VERSION 5.7 ;
  NOWIREEXTENSIONATPIN ON ;
  DIVIDERCHAR "/" ;
  BUSBITCHARS "[]" ;
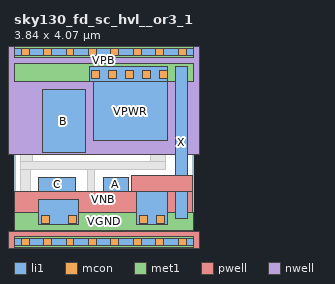
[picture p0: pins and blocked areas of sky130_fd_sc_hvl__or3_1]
MACRO sky130_fd_sc_hvl__or3_1
  CLASS BLOCK ;
  FOREIGN sky130_fd_sc_hvl__or3_1 ;
  ORIGIN 0.000 0.000 ;
  SIZE 3.840 BY 4.070 ;
  PIN A
    ANTENNAGATEAREA 0.420000 ;
    PORT
      LAYER li1 ;
        RECT 1.915 1.080 2.450 1.390 ;
    END
  END A
  PIN B
    ANTENNAGATEAREA 0.420000 ;
    PORT
      LAYER li1 ;
        RECT 0.605 1.910 1.535 3.260 ;
    END
  END B
  PIN C
    ANTENNAGATEAREA 0.420000 ;
    PORT
      LAYER li1 ;
        RECT 0.530 1.080 1.315 1.390 ;
    END
  END C
  PIN VGND
    USE GROUND ;
    PORT
      LAYER li1 ;
        RECT 0.530 0.365 1.385 0.910 ;
        RECT 2.620 0.365 3.290 1.325 ;
      LAYER mcon ;
        RECT 0.580 0.395 0.750 0.565 ;
        RECT 1.165 0.395 1.335 0.565 ;
        RECT 2.690 0.395 2.860 0.565 ;
        RECT 3.050 0.395 3.220 0.565 ;
      LAYER met1 ;
        RECT 0.000 0.255 3.840 0.625 ;
    END
  END VGND
  PIN VNB
    ANTENNADIFFAREA 0.652800 ;
    PORT
      LAYER pwell ;
        RECT 2.510 1.085 3.820 1.415 ;
        RECT 0.020 0.215 3.820 1.085 ;
        RECT -0.130 -0.215 3.970 0.215 ;
      LAYER li1 ;
        RECT 0.000 -0.085 3.840 0.085 ;
      LAYER mcon ;
        RECT 0.155 -0.085 0.325 0.085 ;
        RECT 0.635 -0.085 0.805 0.085 ;
        RECT 1.115 -0.085 1.285 0.085 ;
        RECT 1.595 -0.085 1.765 0.085 ;
        RECT 2.075 -0.085 2.245 0.085 ;
        RECT 2.555 -0.085 2.725 0.085 ;
        RECT 3.035 -0.085 3.205 0.085 ;
        RECT 3.515 -0.085 3.685 0.085 ;
      LAYER met1 ;
        RECT 0.000 -0.115 3.840 0.115 ;
    END
  END VNB
  PIN VPB
    ANTENNADIFFAREA 0.652800 ;
    PORT
      LAYER nwell ;
        RECT -0.330 1.885 4.170 4.485 ;
      LAYER li1 ;
        RECT 0.000 3.985 3.840 4.155 ;
      LAYER mcon ;
        RECT 0.155 3.985 0.325 4.155 ;
        RECT 0.635 3.985 0.805 4.155 ;
        RECT 1.115 3.985 1.285 4.155 ;
        RECT 1.595 3.985 1.765 4.155 ;
        RECT 2.075 3.985 2.245 4.155 ;
        RECT 2.555 3.985 2.725 4.155 ;
        RECT 3.035 3.985 3.205 4.155 ;
        RECT 3.515 3.985 3.685 4.155 ;
      LAYER met1 ;
        RECT 0.000 3.955 3.840 4.185 ;
    END
  END VPB
  PIN VPWR
    USE POWER ;
    PORT
      LAYER li1 ;
        RECT 1.620 3.430 3.280 3.755 ;
        RECT 1.705 2.175 3.280 3.430 ;
      LAYER mcon ;
        RECT 1.670 3.505 1.840 3.675 ;
        RECT 2.030 3.505 2.200 3.675 ;
        RECT 2.390 3.505 2.560 3.675 ;
        RECT 2.750 3.505 2.920 3.675 ;
        RECT 3.110 3.505 3.280 3.675 ;
      LAYER met1 ;
        RECT 0.000 3.445 3.840 3.815 ;
    END
  END VPWR
  PIN X
    ANTENNADIFFAREA 0.626250 ;
    PORT
      LAYER li1 ;
        RECT 3.460 0.495 3.715 3.755 ;
    END
  END X
  OBS
      LAYER li1 ;
        RECT 0.145 1.730 0.395 2.780 ;
        RECT 2.925 1.730 3.255 1.935 ;
        RECT 0.145 1.560 3.255 1.730 ;
        RECT 0.145 0.495 0.360 1.560 ;
        RECT 1.565 0.910 1.735 1.560 ;
        RECT 1.565 0.495 1.965 0.910 ;
  END
END sky130_fd_sc_hvl__or3_1
END LIBRARY

